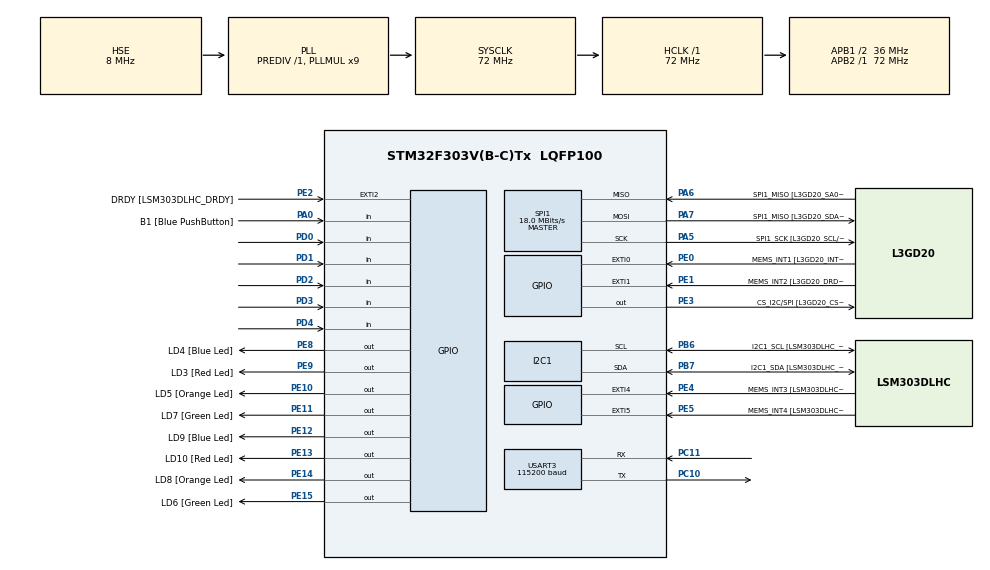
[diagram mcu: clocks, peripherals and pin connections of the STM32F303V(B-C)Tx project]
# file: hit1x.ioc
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I2C1.Timing-I2C=0x2000090E
Mcu.Family=STM32F3
Mcu.Name=STM32F303V(B-C)Tx
Mcu.Package=LQFP100
NVIC.PriorityGroup=NVIC_PRIORITYGROUP_0
PA0.GPIO_Label=B1 [Blue PushButton]
PA0.Signal=GPIO_Input
PA11.GPIO_Label=DM
PA11.Signal=USB_DM
PA12.GPIO_Label=DP
PA12.Signal=USB_DP
PA13.GPIO_Label=SWDIO
PA13.Mode=Serial_Wire
PA13.Signal=SYS_JTMS-SWDIO
PA14.GPIO_Label=SWCLK
PA14.Mode=Serial_Wire
PA14.Signal=SYS_JTCK-SWCLK
PA5.GPIO_Label=SPI1_SCK [L3GD20_SCL/SPC]
PA5.Mode=Full_Duplex_Master
PA5.Signal=SPI1_SCK
PA6.GPIO_Label=SPI1_MISO [L3GD20_SA0/SDO]
PA6.Mode=Full_Duplex_Master
PA6.Signal=SPI1_MISO
PA7.GPIO_Label=SPI1_MISO [L3GD20_SDA/SDI/SDO]
PA7.Mode=Full_Duplex_Master
PA7.Signal=SPI1_MOSI
PB3.GPIO_Label=SWO
PB3.Signal=SYS_JTDO-TRACESWO
PB6.GPIO_Label=I2C1_SCL [LSM303DLHC_SCL]
PB6.Mode=I2C
PB6.Signal=I2C1_SCL
PB7.GPIO_Label=I2C1_SDA [LSM303DLHC_SDA]
PB7.Mode=I2C
PB7.Signal=I2C1_SDA
PC10.GPIO_PuPd=GPIO_PULLUP
PC10.Mode=Asynchronous
PC10.Signal=USART3_TX
PC11.GPIO_PuPd=GPIO_PULLUP
PC11.Mode=Asynchronous
PC11.Signal=USART3_RX
PC14-OSC32_IN.GPIO_Label=OSC32_IN
PC14-OSC32_IN.Signal=RCC_OSC32_IN
PC15-OSC32_OUT.GPIO_Label=OSC32_OUT
PC15-OSC32_OUT.Signal=RCC_OSC32_OUT
PD0.Signal=GPIO_Input
PD1.Signal=GPIO_Input
PD2.Signal=GPIO_Input
PD3.Signal=GPIO_Input
PD4.Signal=GPIO_Input
PE0.GPIO_Label=MEMS_INT1 [L3GD20_INT1]
PE0.GPIO_ModeDefaultEXTI=GPIO_MODE_EVT_RISING
PE0.Signal=GPXTI0
PE1.GPIO_Label=MEMS_INT2 [L3GD20_DRDY/INT2]
PE1.GPIO_ModeDefaultEXTI=GPIO_MODE_EVT_RISING
PE1.Signal=GPXTI1
PE10.GPIO_Label=LD5 [Orange Led]
PE10.Signal=GPIO_Output
PE11.GPIO_Label=LD7 [Green Led]
PE11.Signal=GPIO_Output
PE12.GPIO_Label=LD9 [Blue Led]
PE12.Signal=GPIO_Output
PE13.GPIO_Label=LD10 [Red Led]
PE13.Signal=GPIO_Output
PE14.GPIO_Label=LD8 [Orange Led]
PE14.Signal=GPIO_Output
PE15.GPIO_Label=LD6 [Green Led]
PE15.PinState=GPIO_PIN_SET
PE15.Signal=GPIO_Output
PE2.GPIO_Label=DRDY [LSM303DLHC_DRDY]
PE2.GPIO_ModeDefaultEXTI=GPIO_MODE_EVT_RISING
PE2.Signal=GPXTI2
PE3.GPIO_Label=CS_I2C/SPI [L3GD20_CS_I2C/SPI]
PE3.Signal=GPIO_Output
PE4.GPIO_Label=MEMS_INT3 [LSM303DLHC_INT1]
PE4.GPIO_ModeDefaultEXTI=GPIO_MODE_EVT_RISING
PE4.Signal=GPXTI4
PE5.GPIO_Label=MEMS_INT4 [LSM303DLHC_INT2]
PE5.GPIO_ModeDefaultEXTI=GPIO_MODE_EVT_RISING
PE5.Signal=GPXTI5
PE8.GPIO_Label=LD4 [Blue Led]
PE8.Signal=GPIO_Output
PE9.GPIO_Label=LD3 [Red Led]
PE9.Signal=GPIO_Output
PF0-OSC_IN.GPIO_Label=OSC_IN
PF0-OSC_IN.Mode=HSE-External-Oscillator
PF0-OSC_IN.Signal=RCC_OSC_IN
PF1-OSC_OUT.GPIO_Label=OSC_OUT
PF1-OSC_OUT.Mode=HSE-External-Oscillator
PF1-OSC_OUT.Signal=RCC_OSC_OUT
ProjectManager.HeapSize=0x200
ProjectManager.StackSize=0x400
ProjectManager.TargetToolchain=STM32CubeIDE
RCC.AHBFreq_Value=72000000
RCC.APB1CLKDivider=RCC_HCLK_DIV2
RCC.APB1Freq_Value=36000000
RCC.APB1TimFreq_Value=72000000
RCC.APB2Freq_Value=72000000
RCC.APB2TimFreq_Value=72000000
RCC.CortexFreq_Value=72000000
RCC.HCLKFreq_Value=72000000
RCC.HSE_VALUE=8000000
RCC.HSI_VALUE=8000000
RCC.LSE_VALUE=32768
RCC.PLLMUL=RCC_PLL_MUL9
RCC.PLLSourceVirtual=RCC_PLLSOURCE_HSE
RCC.PRESCALERUSB=RCC_USBCLKSOURCE_PLL_DIV1_5
RCC.SYSCLKFreq_VALUE=72000000
RCC.SYSCLKSourceVirtual=RCC_SYSCLKSOURCE_PLLCLK
RCC.USBFreq_Value=48000000
SPI1.BaudRatePrescaler=SPI_BAUDRATEPRESCALER_4
SPI1.BaudRatePrescaler-Full_Duplex_Master=SPI_BAUDRATEPRESCALER_2
SPI1.CalculateBaudRate=18.0 MBits/s
SPI1.CalculateBaudRate-Full_Duplex_Master=24.0 MBits/s
SPI1.Direction=SPI_DIRECTION_2LINES
SPI1.Mode=SPI_MODE_MASTER
SPI1.Mode-Full_Duplex_Master=SPI_MODE_MASTER
SPI1.VirtualType=VM_MASTER
USART3.BaudRate=115200
USART3.StopBits=STOPBITS_2
USART3.VirtualMode-Asynchronous=VM_ASYNC
board=STM32F3DISCOVERY

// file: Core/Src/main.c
/* USER CODE BEGIN Header */
/**
  ******************************************************************************
  * @file           : main.c
  * @brief          : Main program body
  ******************************************************************************
  * @attention
  *
  * <h2><center>&copy; Copyright (c) 2020 STMicroelectronics.
  * All rights reserved.</center></h2>
  *
  * This software component is licensed by ST under BSD 3-Clause license,
  * the "License"; You may not use this file except in compliance with the
  * License. You may obtain a copy of the License at:
  *                        opensource.org/licenses/BSD-3-Clause
  *
  ******************************************************************************
  */
/* USER CODE END Header */

#include "main.h"

I2C_HandleTypeDef hi2c1;

SPI_HandleTypeDef hspi1;

UART_HandleTypeDef huart3;

void SystemClock_Config(void);
static void MX_GPIO_Init(void);
static void MX_I2C1_Init(void);
static void MX_SPI1_Init(void);
static void MX_USART3_UART_Init(void);

int main(void)  __attribute__ ((section (".sramcode")));
int main(void)
{

  /* MCU Configuration--------------------------------------------------------*/

  /* Reset of all peripherals, Initializes the Flash interface and the Systick. */
  HAL_Init();

  /* Configure the system clock */
  SystemClock_Config();

  /* Initialize all configured peripherals */
  MX_GPIO_Init();
  MX_I2C1_Init();
  MX_SPI1_Init();
  MX_USART3_UART_Init();

  /* Infinite loop */
  /* USER CODE BEGIN WHILE */

  while (1)
  {
		//D0, D1: Power, D4: Reset, D2: BOOT0
		__asm__ volatile("start1: ldr r4, =0x48000c10"); //GPIOD input register
		__asm__ volatile("ldr r5, =0x48000c00"); //GPIOD MODER
		__asm__ volatile("ldr r6, =0x48000010"); //GPIOA MODER
		__asm__ volatile("ldr r7, =0x48000c18"); //GPIOD BSSR
		__asm__ volatile("ldr r8, =0x48001018"); //GPIOE BSSR
		__asm__ volatile("mov r0, #3"); //set high PD0+PD1
		__asm__ volatile("str r0, [r7]");
		__asm__ volatile("mov r0, #4"); //set high PD2
		__asm__ volatile("str r0, [r7]");
		__asm__ volatile("mov r0, #0x0015"); //output PD0+PD1+PD2
		__asm__ volatile("str r0, [r5]");

		__asm__ volatile("start2: ldr r0, =0x20000000"); //red off
		__asm__ volatile("str r0, [r8]"); //led off

		//wait for button
		__asm__ volatile("wbtn: ldr r0, [r6]"); //get inputs
		__asm__ volatile("ands r0, 0x01");
		__asm__ volatile("beq wbtn");

		//set LEDs
		__asm__ volatile("ldr r0, =0x00004000"); //on
		__asm__ volatile("str r0, [r8]"); //led on

		__asm__ volatile("mov r0, #0x30000"); //set low PD0+PD1
		__asm__ volatile("str r0, [r7]");

		//wait for some time until reset triggers
		__asm__ volatile("l1: ldr r0, [r4]"); //get inputs
		__asm__ volatile("ands r0, #0x010");
		__asm__ volatile("bne l1");

		__asm__ volatile("mov r0, #0x3"); //set high PD0+PD1
		__asm__ volatile("str r0, [r7]");

		//let the SRAM firmware run
		__asm__ volatile("mov r1, #0x100000");
		__asm__ volatile("wait1: subs r1, r1, #1");
		__asm__ volatile("bne wait1");

		__asm__ volatile("ldr r0, =0x40001000"); //on
		__asm__ volatile("str r0, [r8]"); //led on

		__asm__ volatile("mov r0, #0x40000"); //set low PD2
		__asm__ volatile("str r0, [r7]");

		__asm__ volatile("mov r0, #0x100000"); //set low PD4
		__asm__ volatile("str r0, [r7]");
		__asm__ volatile("mov r0, #0x0115"); //output PD0+PD1+PD2+PD4
		__asm__ volatile("str r0, [r5]");

		//wait for reset release
		__asm__ volatile("mov r1, #0x100000");
		__asm__ volatile("wait2: subs r1, r1, #1");
		__asm__ volatile("bne wait2");

		__asm__ volatile("mov r0, #0x0015"); //output PD0+PD1+PD2
		__asm__ volatile("str r0, [r5]");

		//set LEDs
		__asm__ volatile("ldr r0, =0x10002000"); //red on, blue off
		__asm__ volatile("str r0, [r8]"); //led off

		//let the SRAM firmware run
		__asm__ volatile("mov r1, #0xF00000");
		__asm__ volatile("wait3: subs r1, r1, #1");
		__asm__ volatile("bne wait3");

		__asm__ volatile("mov r0, #0x40000"); //set low PD2
		__asm__ volatile("str r0, [r7]");

		__asm__ volatile("b start2");

  }

  /* USER CODE END 3 */
}

void SystemClock_Config(void)
{
  RCC_OscInitTypeDef RCC_OscInitStruct = {0};
  RCC_ClkInitTypeDef RCC_ClkInitStruct = {0};
  RCC_PeriphCLKInitTypeDef PeriphClkInit = {0};

  /** Initializes the CPU, AHB and APB busses clocks
  */
  RCC_OscInitStruct.OscillatorType = RCC_OSCILLATORTYPE_HSI;
  RCC_OscInitStruct.HSEState = RCC_HSE_OFF;
  RCC_OscInitStruct.HSEPredivValue = RCC_HSE_PREDIV_DIV1;
  RCC_OscInitStruct.HSIState = RCC_HSI_ON;
  RCC_OscInitStruct.HSICalibrationValue = RCC_HSICALIBRATION_DEFAULT;
  RCC_OscInitStruct.PLL.PLLState = RCC_PLL_ON;
  RCC_OscInitStruct.PLL.PLLSource = RCC_PLLSOURCE_HSE;
  RCC_OscInitStruct.PLL.PLLMUL = RCC_PLL_MUL9;
  if (HAL_RCC_OscConfig(&RCC_OscInitStruct) != HAL_OK)
  {
    Error_Handler();
  }
  /** Initializes the CPU, AHB and APB busses clocks
  */
  RCC_ClkInitStruct.ClockType = RCC_CLOCKTYPE_HCLK|RCC_CLOCKTYPE_SYSCLK
                              |RCC_CLOCKTYPE_PCLK1|RCC_CLOCKTYPE_PCLK2;
  RCC_ClkInitStruct.SYSCLKSource = RCC_SYSCLKSOURCE_PLLCLK;
  RCC_ClkInitStruct.AHBCLKDivider = RCC_SYSCLK_DIV1;
  RCC_ClkInitStruct.APB1CLKDivider = RCC_HCLK_DIV2;
  RCC_ClkInitStruct.APB2CLKDivider = RCC_HCLK_DIV1;

  if (HAL_RCC_ClockConfig(&RCC_ClkInitStruct, FLASH_LATENCY_2) != HAL_OK)
  {
    Error_Handler();
  }
  PeriphClkInit.PeriphClockSelection = RCC_PERIPHCLK_USART3|RCC_PERIPHCLK_I2C1;
  PeriphClkInit.Usart3ClockSelection = RCC_USART3CLKSOURCE_PCLK1;
  PeriphClkInit.I2c1ClockSelection = RCC_I2C1CLKSOURCE_HSI;
  if (HAL_RCCEx_PeriphCLKConfig(&PeriphClkInit) != HAL_OK)
  {
    Error_Handler();
  }
}

static void MX_I2C1_Init(void)
{

  hi2c1.Instance = I2C1;
  hi2c1.Init.Timing = 0x2000090E;
  hi2c1.Init.OwnAddress1 = 0;
  hi2c1.Init.AddressingMode = I2C_ADDRESSINGMODE_7BIT;
  hi2c1.Init.DualAddressMode = I2C_DUALADDRESS_DISABLE;
  hi2c1.Init.OwnAddress2 = 0;
  hi2c1.Init.OwnAddress2Masks = I2C_OA2_NOMASK;
  hi2c1.Init.GeneralCallMode = I2C_GENERALCALL_DISABLE;
  hi2c1.Init.NoStretchMode = I2C_NOSTRETCH_DISABLE;
  if (HAL_I2C_Init(&hi2c1) != HAL_OK)
  {
    Error_Handler();
  }
  /** Configure Analogue filter
  */
  if (HAL_I2CEx_ConfigAnalogFilter(&hi2c1, I2C_ANALOGFILTER_ENABLE) != HAL_OK)
  {
    Error_Handler();
  }
  /** Configure Digital filter
  */
  if (HAL_I2CEx_ConfigDigitalFilter(&hi2c1, 0) != HAL_OK)
  {
    Error_Handler();
  }

}

static void MX_SPI1_Init(void)
{

  /* SPI1 parameter configuration*/
  hspi1.Instance = SPI1;
  hspi1.Init.Mode = SPI_MODE_MASTER;
  hspi1.Init.Direction = SPI_DIRECTION_2LINES;
  hspi1.Init.DataSize = SPI_DATASIZE_4BIT;
  hspi1.Init.CLKPolarity = SPI_POLARITY_LOW;
  hspi1.Init.CLKPhase = SPI_PHASE_1EDGE;
  hspi1.Init.NSS = SPI_NSS_SOFT;
  hspi1.Init.BaudRatePrescaler = SPI_BAUDRATEPRESCALER_4;
  hspi1.Init.FirstBit = SPI_FIRSTBIT_MSB;
  hspi1.Init.TIMode = SPI_TIMODE_DISABLE;
  hspi1.Init.CRCCalculation = SPI_CRCCALCULATION_DISABLE;
  hspi1.Init.CRCPolynomial = 7;
  hspi1.Init.CRCLength = SPI_CRC_LENGTH_DATASIZE;
  hspi1.Init.NSSPMode = SPI_NSS_PULSE_ENABLE;
  if (HAL_SPI_Init(&hspi1) != HAL_OK)
  {
    Error_Handler();
  }

}

static void MX_USART3_UART_Init(void)
{

  huart3.Instance = USART3;
  huart3.Init.BaudRate = 115200;
  huart3.Init.WordLength = UART_WORDLENGTH_8B;
  huart3.Init.StopBits = UART_STOPBITS_2;
  huart3.Init.Parity = UART_PARITY_NONE;
  huart3.Init.Mode = UART_MODE_TX_RX;
  huart3.Init.HwFlowCtl = UART_HWCONTROL_NONE;
  huart3.Init.OverSampling = UART_OVERSAMPLING_16;
  huart3.Init.OneBitSampling = UART_ONE_BIT_SAMPLE_DISABLE;
  huart3.AdvancedInit.AdvFeatureInit = UART_ADVFEATURE_NO_INIT;
  if (HAL_UART_Init(&huart3) != HAL_OK)
  {
    Error_Handler();
  }

}

static void MX_GPIO_Init(void)
{
  GPIO_InitTypeDef GPIO_InitStruct = {0};

  /* GPIO Ports Clock Enable */
  __HAL_RCC_GPIOE_CLK_ENABLE();
  __HAL_RCC_GPIOC_CLK_ENABLE();
  __HAL_RCC_GPIOF_CLK_ENABLE();
  __HAL_RCC_GPIOA_CLK_ENABLE();
  __HAL_RCC_GPIOD_CLK_ENABLE();
  __HAL_RCC_GPIOB_CLK_ENABLE();

  /*Configure GPIO pin Output Level */
  HAL_GPIO_WritePin(GPIOE, CS_I2C_SPI_Pin|LD4_Pin|LD3_Pin|LD5_Pin
                          |LD7_Pin|LD9_Pin|LD10_Pin|LD8_Pin, GPIO_PIN_RESET);

  /*Configure GPIO pin Output Level */
  HAL_GPIO_WritePin(LD6_GPIO_Port, LD6_Pin, GPIO_PIN_SET);

  /*Configure GPIO pins : DRDY_Pin MEMS_INT3_Pin MEMS_INT4_Pin MEMS_INT1_Pin
                           MEMS_INT2_Pin */
  GPIO_InitStruct.Pin = DRDY_Pin|MEMS_INT3_Pin|MEMS_INT4_Pin|MEMS_INT1_Pin
                          |MEMS_INT2_Pin;
  GPIO_InitStruct.Mode = GPIO_MODE_EVT_RISING;
  GPIO_InitStruct.Pull = GPIO_NOPULL;
  HAL_GPIO_Init(GPIOE, &GPIO_InitStruct);

  /*Configure GPIO pins : CS_I2C_SPI_Pin LD4_Pin LD3_Pin LD5_Pin
                           LD7_Pin LD9_Pin LD10_Pin LD8_Pin
                           LD6_Pin */
  GPIO_InitStruct.Pin = CS_I2C_SPI_Pin|LD4_Pin|LD3_Pin|LD5_Pin
                          |LD7_Pin|LD9_Pin|LD10_Pin|LD8_Pin
                          |LD6_Pin;
  GPIO_InitStruct.Mode = GPIO_MODE_OUTPUT_PP;
  GPIO_InitStruct.Pull = GPIO_NOPULL;
  GPIO_InitStruct.Speed = GPIO_SPEED_FREQ_LOW;
  HAL_GPIO_Init(GPIOE, &GPIO_InitStruct);

  /*Configure GPIO pin : B1_Pin */
  GPIO_InitStruct.Pin = B1_Pin;
  GPIO_InitStruct.Mode = GPIO_MODE_INPUT;
  GPIO_InitStruct.Pull = GPIO_NOPULL;
  HAL_GPIO_Init(B1_GPIO_Port, &GPIO_InitStruct);

  /*Configure GPIO pins : DM_Pin DP_Pin */
  GPIO_InitStruct.Pin = DM_Pin|DP_Pin;
  GPIO_InitStruct.Mode = GPIO_MODE_AF_PP;
  GPIO_InitStruct.Pull = GPIO_NOPULL;
  GPIO_InitStruct.Speed = GPIO_SPEED_FREQ_HIGH;
  GPIO_InitStruct.Alternate = GPIO_AF14_USB;
  HAL_GPIO_Init(GPIOA, &GPIO_InitStruct);

  /*Configure GPIO pins : PD0 PD1 PD2 PD3
                           PD4 PD5 PD6 PD7 */
  GPIO_InitStruct.Pin = GPIO_PIN_0|GPIO_PIN_1|GPIO_PIN_2|GPIO_PIN_3
		  	  	  	   |GPIO_PIN_4|GPIO_PIN_5|GPIO_PIN_6|GPIO_PIN_7;
  GPIO_InitStruct.Mode = GPIO_MODE_INPUT;
  GPIO_InitStruct.Pull = GPIO_PULLUP;
  HAL_GPIO_Init(GPIOD, &GPIO_InitStruct);

}

void Error_Handler(void)
{
}

/************************ (C) COPYRIGHT STMicroelectronics *****END OF FILE****/
